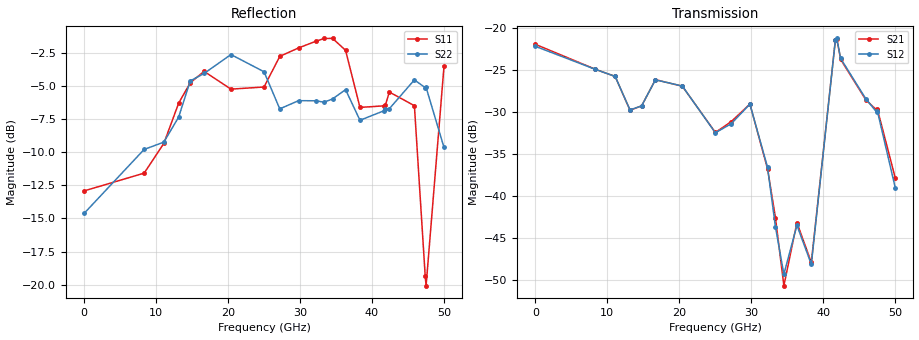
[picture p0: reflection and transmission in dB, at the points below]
!Keysight Technologies,N5245B,MY58422270,A.16.20.02
!Date: Thursday, March 05, 2026 01:27:20
!Correction: S11(C  2-Port  )
!S21(C  2-Port  )
!S12(C  2-Port  )
!S22(C  2-Port  )
!S2P File: Measurements: S11, S21, S12, S22:
# Hz S  dB  R 50
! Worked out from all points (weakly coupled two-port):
!   3201 points, 10 MHz to 50 GHz, reference 50 ohm
!   highest |S21| = -21.30 dB at 41.86 GHz (marker M1); lowest = -50.7 dB at 34.52 GHz (marker M2)
!   lowest |S11| = -20.1 dB at 47.52 GHz (marker M3), VSWR 1.22, Z = 45.6 + j8.45 ohm
!   |S11| at or under -10 dB: start of sweep to 10.13 GHz; 11.35 GHz to 11.92 GHz (570.5 MHz wide, 4.9 % of centre); 46.66 GHz to 48.28 GHz (1.622 GHz wide, 3.42 % of centre)
!   |S22| runs from -18.6 to -2.6 dB; largest |S21 - S12| = 0.0081
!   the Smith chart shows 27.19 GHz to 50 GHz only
!   S11 on the Smith chart (normalised r, x): 27.19 GHz: 0.18, +0.36; 32.25 GHz: 0.41, +1.82; 36.33 GHz: 2.49, -3.46; 42.41 GHz: 1.02, -1.27; 47.39 GHz: 0.84, +0.12; 50 GHz: 0.62, -1.35
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1e7  -12.92 -4.9  -21.99 4.0  -22.23 3.8  -14.62 34.9
8.352081e9  -11.58 175.0  -24.96 29.4  -24.97 29.2  -9.79 -170.9
1.108591e10  -9.34 109.3  -25.81 -72.8  -25.81 -72.9  -9.24 86.0
1.3148e10  -6.30 64.8  -29.83 -130.9  -29.79 -130.5  -7.35 -22.2
1.475705e10  -4.76 13.3  -29.31 -152.5  -29.31 -152.8  -4.62 -90.4
1.667854e10  -3.90 -43.8  -26.19 157.4  -26.21 157.8  -4.06 -141.1
2.041217e10  -5.24 -121.5  -26.97 39.8  -26.95 39.2  -2.63 154.9
2.5005e10  -5.08 179.9  -32.47 -66.5  -32.51 -65.5  -3.93 71.6
2.719206e10  -2.77 139.7  -31.19 -113.5  -31.44 -113.6  -6.73 32.4
2.980092e10  -2.13 94.4  -29.09 159.6  -29.11 159.9  -6.11 -27.6
3.225355e10  -1.62 55.6  -36.80 49.0  -36.62 52.5  -6.12 -102.5
3.334708e10  -1.42 36.1  -42.59 5.7  -43.68 6.1  -6.23 -126.8
3.451872e10  -1.41 15.0  -50.69 -120.8  -49.33 -115.6  -5.98 -151.6
3.633086e10  -2.31 -22.0  -43.19 116.3  -43.51 115.0  -5.28 174.4
3.833046e10  -6.62 -22.3  -47.93 -76.2  -48.14 78.5  -7.59 140.8
4.167354e10  -6.50 -52.6  -21.46 -54.6  -21.48 -54.8  -6.87 115.1
4.1861e10  -6.45 -52.4  -21.30 -72.4  -21.28 -72.5  -6.73 113.3
4.240777e10  -5.46 -56.9  -23.79 -114.0  -23.67 -114.0  -6.72 109.8
4.589145e10  -6.49 -117.0  -28.58 51.2  -28.46 50.1  -4.54 62.5
4.739115e10  -19.33 141.0  -29.79 2.5  -30.03 2.9  -5.13 43.4
4.751612e10  -20.07 112.4  -29.73 0.4  -29.96 1.2  -5.11 42.1
5e10  -3.53 -65.7  -37.91 -138.2  -39.08 -126.7  -9.64 4.8
